VERSION 5.7 ;
BUSBITCHARS "[]" ;
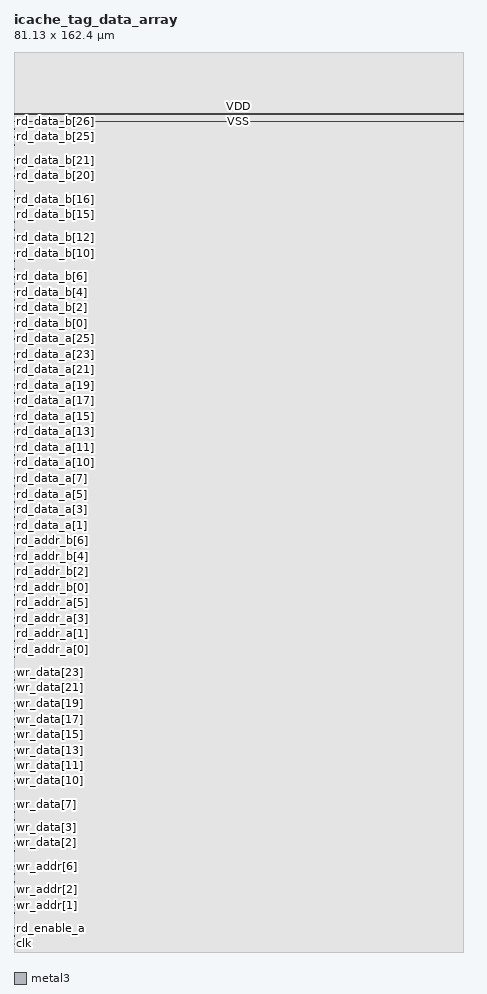
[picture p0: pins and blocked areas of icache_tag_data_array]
MACRO icache_tag_data_array
  FOREIGN icache_tag_data_array 0 0 ;
  SYMMETRY X Y R90 ;
  SIZE 81.130 BY 162.400 ;
  CLASS BLOCK ;
  PIN clk
    DIRECTION INPUT ;
    USE SIGNAL ;
    SHAPE ABUTMENT ;
    PORT
      LAYER metal3 ;
      RECT 0.000 1.400 0.140 1.540 ;
    END
  END clk
  PIN wr_enable
    DIRECTION INPUT ;
    USE SIGNAL ;
    SHAPE ABUTMENT ;
    PORT
      LAYER metal3 ;
      RECT 0.000 2.800 0.140 2.940 ;
    END
  END wr_enable
  PIN rd_enable_a
    DIRECTION INPUT ;
    USE SIGNAL ;
    SHAPE ABUTMENT ;
    PORT
      LAYER metal3 ;
      RECT 0.000 4.200 0.140 4.340 ;
    END
  END rd_enable_a
  PIN rd_enable_b
    DIRECTION INPUT ;
    USE SIGNAL ;
    SHAPE ABUTMENT ;
    PORT
      LAYER metal3 ;
      RECT 0.000 5.600 0.140 5.740 ;
    END
  END rd_enable_b
  PIN wr_addr[0]
    DIRECTION INPUT ;
    USE SIGNAL ;
    SHAPE ABUTMENT ;
    PORT
      LAYER metal3 ;
      RECT 0.000 7.000 0.140 7.140 ;
    END
  END wr_addr[0]
  PIN wr_addr[1]
    DIRECTION INPUT ;
    USE SIGNAL ;
    SHAPE ABUTMENT ;
    PORT
      LAYER metal3 ;
      RECT 0.000 8.400 0.140 8.540 ;
    END
  END wr_addr[1]
  PIN wr_addr[2]
    DIRECTION INPUT ;
    USE SIGNAL ;
    SHAPE ABUTMENT ;
    PORT
      LAYER metal3 ;
      RECT 0.000 9.800 0.140 9.940 ;
    END
  END wr_addr[2]
  PIN wr_addr[3]
    DIRECTION INPUT ;
    USE SIGNAL ;
    SHAPE ABUTMENT ;
    PORT
      LAYER metal3 ;
      RECT 0.000 11.200 0.140 11.340 ;
    END
  END wr_addr[3]
  PIN wr_addr[4]
    DIRECTION INPUT ;
    USE SIGNAL ;
    SHAPE ABUTMENT ;
    PORT
      LAYER metal3 ;
      RECT 0.000 12.600 0.140 12.740 ;
    END
  END wr_addr[4]
  PIN wr_addr[5]
    DIRECTION INPUT ;
    USE SIGNAL ;
    SHAPE ABUTMENT ;
    PORT
      LAYER metal3 ;
      RECT 0.000 14.000 0.140 14.140 ;
    END
  END wr_addr[5]
  PIN wr_addr[6]
    DIRECTION INPUT ;
    USE SIGNAL ;
    SHAPE ABUTMENT ;
    PORT
      LAYER metal3 ;
      RECT 0.000 15.400 0.140 15.540 ;
    END
  END wr_addr[6]
  PIN wr_data[0]
    DIRECTION INPUT ;
    USE SIGNAL ;
    SHAPE ABUTMENT ;
    PORT
      LAYER metal3 ;
      RECT 0.000 16.800 0.140 16.940 ;
    END
  END wr_data[0]
  PIN wr_data[1]
    DIRECTION INPUT ;
    USE SIGNAL ;
    SHAPE ABUTMENT ;
    PORT
      LAYER metal3 ;
      RECT 0.000 18.200 0.140 18.340 ;
    END
  END wr_data[1]
  PIN wr_data[2]
    DIRECTION INPUT ;
    USE SIGNAL ;
    SHAPE ABUTMENT ;
    PORT
      LAYER metal3 ;
      RECT 0.000 19.600 0.140 19.740 ;
    END
  END wr_data[2]
  PIN wr_data[3]
    DIRECTION INPUT ;
    USE SIGNAL ;
    SHAPE ABUTMENT ;
    PORT
      LAYER metal3 ;
      RECT 0.000 21.000 0.140 21.140 ;
    END
  END wr_data[3]
  PIN wr_data[4]
    DIRECTION INPUT ;
    USE SIGNAL ;
    SHAPE ABUTMENT ;
    PORT
      LAYER metal3 ;
      RECT 0.000 22.400 0.140 22.540 ;
    END
  END wr_data[4]
  PIN wr_data[5]
    DIRECTION INPUT ;
    USE SIGNAL ;
    SHAPE ABUTMENT ;
    PORT
      LAYER metal3 ;
      RECT 0.000 23.800 0.140 23.940 ;
    END
  END wr_data[5]
  PIN wr_data[6]
    DIRECTION INPUT ;
    USE SIGNAL ;
    SHAPE ABUTMENT ;
    PORT
      LAYER metal3 ;
      RECT 0.000 25.200 0.140 25.340 ;
    END
  END wr_data[6]
  PIN wr_data[7]
    DIRECTION INPUT ;
    USE SIGNAL ;
    SHAPE ABUTMENT ;
    PORT
      LAYER metal3 ;
      RECT 0.000 26.600 0.140 26.740 ;
    END
  END wr_data[7]
  PIN wr_data[8]
    DIRECTION INPUT ;
    USE SIGNAL ;
    SHAPE ABUTMENT ;
    PORT
      LAYER metal3 ;
      RECT 0.000 28.000 0.140 28.140 ;
    END
  END wr_data[8]
  PIN wr_data[9]
    DIRECTION INPUT ;
    USE SIGNAL ;
    SHAPE ABUTMENT ;
    PORT
      LAYER metal3 ;
      RECT 0.000 29.400 0.140 29.540 ;
    END
  END wr_data[9]
  PIN wr_data[10]
    DIRECTION INPUT ;
    USE SIGNAL ;
    SHAPE ABUTMENT ;
    PORT
      LAYER metal3 ;
      RECT 0.000 30.800 0.140 30.940 ;
    END
  END wr_data[10]
  PIN wr_data[11]
    DIRECTION INPUT ;
    USE SIGNAL ;
    SHAPE ABUTMENT ;
    PORT
      LAYER metal3 ;
      RECT 0.000 32.200 0.140 32.340 ;
    END
  END wr_data[11]
  PIN wr_data[12]
    DIRECTION INPUT ;
    USE SIGNAL ;
    SHAPE ABUTMENT ;
    PORT
      LAYER metal3 ;
      RECT 0.000 33.600 0.140 33.740 ;
    END
  END wr_data[12]
  PIN wr_data[13]
    DIRECTION INPUT ;
    USE SIGNAL ;
    SHAPE ABUTMENT ;
    PORT
      LAYER metal3 ;
      RECT 0.000 35.000 0.140 35.140 ;
    END
  END wr_data[13]
  PIN wr_data[14]
    DIRECTION INPUT ;
    USE SIGNAL ;
    SHAPE ABUTMENT ;
    PORT
      LAYER metal3 ;
      RECT 0.000 36.400 0.140 36.540 ;
    END
  END wr_data[14]
  PIN wr_data[15]
    DIRECTION INPUT ;
    USE SIGNAL ;
    SHAPE ABUTMENT ;
    PORT
      LAYER metal3 ;
      RECT 0.000 37.800 0.140 37.940 ;
    END
  END wr_data[15]
  PIN wr_data[16]
    DIRECTION INPUT ;
    USE SIGNAL ;
    SHAPE ABUTMENT ;
    PORT
      LAYER metal3 ;
      RECT 0.000 39.200 0.140 39.340 ;
    END
  END wr_data[16]
  PIN wr_data[17]
    DIRECTION INPUT ;
    USE SIGNAL ;
    SHAPE ABUTMENT ;
    PORT
      LAYER metal3 ;
      RECT 0.000 40.600 0.140 40.740 ;
    END
  END wr_data[17]
  PIN wr_data[18]
    DIRECTION INPUT ;
    USE SIGNAL ;
    SHAPE ABUTMENT ;
    PORT
      LAYER metal3 ;
      RECT 0.000 42.000 0.140 42.140 ;
    END
  END wr_data[18]
  PIN wr_data[19]
    DIRECTION INPUT ;
    USE SIGNAL ;
    SHAPE ABUTMENT ;
    PORT
      LAYER metal3 ;
      RECT 0.000 43.400 0.140 43.540 ;
    END
  END wr_data[19]
  PIN wr_data[20]
    DIRECTION INPUT ;
    USE SIGNAL ;
    SHAPE ABUTMENT ;
    PORT
      LAYER metal3 ;
      RECT 0.000 44.800 0.140 44.940 ;
    END
  END wr_data[20]
  PIN wr_data[21]
    DIRECTION INPUT ;
    USE SIGNAL ;
    SHAPE ABUTMENT ;
    PORT
      LAYER metal3 ;
      RECT 0.000 46.200 0.140 46.340 ;
    END
  END wr_data[21]
  PIN wr_data[22]
    DIRECTION INPUT ;
    USE SIGNAL ;
    SHAPE ABUTMENT ;
    PORT
      LAYER metal3 ;
      RECT 0.000 47.600 0.140 47.740 ;
    END
  END wr_data[22]
  PIN wr_data[23]
    DIRECTION INPUT ;
    USE SIGNAL ;
    SHAPE ABUTMENT ;
    PORT
      LAYER metal3 ;
      RECT 0.000 49.000 0.140 49.140 ;
    END
  END wr_data[23]
  PIN wr_data[24]
    DIRECTION INPUT ;
    USE SIGNAL ;
    SHAPE ABUTMENT ;
    PORT
      LAYER metal3 ;
      RECT 0.000 50.400 0.140 50.540 ;
    END
  END wr_data[24]
  PIN wr_data[25]
    DIRECTION INPUT ;
    USE SIGNAL ;
    SHAPE ABUTMENT ;
    PORT
      LAYER metal3 ;
      RECT 0.000 51.800 0.140 51.940 ;
    END
  END wr_data[25]
  PIN wr_data[26]
    DIRECTION INPUT ;
    USE SIGNAL ;
    SHAPE ABUTMENT ;
    PORT
      LAYER metal3 ;
      RECT 0.000 53.200 0.140 53.340 ;
    END
  END wr_data[26]
  PIN rd_addr_a[0]
    DIRECTION INPUT ;
    USE SIGNAL ;
    SHAPE ABUTMENT ;
    PORT
      LAYER metal3 ;
      RECT 0.000 54.600 0.140 54.740 ;
    END
  END rd_addr_a[0]
  PIN rd_addr_a[1]
    DIRECTION INPUT ;
    USE SIGNAL ;
    SHAPE ABUTMENT ;
    PORT
      LAYER metal3 ;
      RECT 0.000 56.000 0.140 56.140 ;
    END
  END rd_addr_a[1]
  PIN rd_addr_a[2]
    DIRECTION INPUT ;
    USE SIGNAL ;
    SHAPE ABUTMENT ;
    PORT
      LAYER metal3 ;
      RECT 0.000 57.400 0.140 57.540 ;
    END
  END rd_addr_a[2]
  PIN rd_addr_a[3]
    DIRECTION INPUT ;
    USE SIGNAL ;
    SHAPE ABUTMENT ;
    PORT
      LAYER metal3 ;
      RECT 0.000 58.800 0.140 58.940 ;
    END
  END rd_addr_a[3]
  PIN rd_addr_a[4]
    DIRECTION INPUT ;
    USE SIGNAL ;
    SHAPE ABUTMENT ;
    PORT
      LAYER metal3 ;
      RECT 0.000 60.200 0.140 60.340 ;
    END
  END rd_addr_a[4]
  PIN rd_addr_a[5]
    DIRECTION INPUT ;
    USE SIGNAL ;
    SHAPE ABUTMENT ;
    PORT
      LAYER metal3 ;
      RECT 0.000 61.600 0.140 61.740 ;
    END
  END rd_addr_a[5]
  PIN rd_addr_a[6]
    DIRECTION INPUT ;
    USE SIGNAL ;
    SHAPE ABUTMENT ;
    PORT
      LAYER metal3 ;
      RECT 0.000 63.000 0.140 63.140 ;
    END
  END rd_addr_a[6]
  PIN rd_addr_b[0]
    DIRECTION INPUT ;
    USE SIGNAL ;
    SHAPE ABUTMENT ;
    PORT
      LAYER metal3 ;
      RECT 0.000 64.400 0.140 64.540 ;
    END
  END rd_addr_b[0]
  PIN rd_addr_b[1]
    DIRECTION INPUT ;
    USE SIGNAL ;
    SHAPE ABUTMENT ;
    PORT
      LAYER metal3 ;
      RECT 0.000 65.800 0.140 65.940 ;
    END
  END rd_addr_b[1]
  PIN rd_addr_b[2]
    DIRECTION INPUT ;
    USE SIGNAL ;
    SHAPE ABUTMENT ;
    PORT
      LAYER metal3 ;
      RECT 0.000 67.200 0.140 67.340 ;
    END
  END rd_addr_b[2]
  PIN rd_addr_b[3]
    DIRECTION INPUT ;
    USE SIGNAL ;
    SHAPE ABUTMENT ;
    PORT
      LAYER metal3 ;
      RECT 0.000 68.600 0.140 68.740 ;
    END
  END rd_addr_b[3]
  PIN rd_addr_b[4]
    DIRECTION INPUT ;
    USE SIGNAL ;
    SHAPE ABUTMENT ;
    PORT
      LAYER metal3 ;
      RECT 0.000 70.000 0.140 70.140 ;
    END
  END rd_addr_b[4]
  PIN rd_addr_b[5]
    DIRECTION INPUT ;
    USE SIGNAL ;
    SHAPE ABUTMENT ;
    PORT
      LAYER metal3 ;
      RECT 0.000 71.400 0.140 71.540 ;
    END
  END rd_addr_b[5]
  PIN rd_addr_b[6]
    DIRECTION INPUT ;
    USE SIGNAL ;
    SHAPE ABUTMENT ;
    PORT
      LAYER metal3 ;
      RECT 0.000 72.800 0.140 72.940 ;
    END
  END rd_addr_b[6]
  PIN rd_data_a[0]
    DIRECTION OUTPUT ;
    USE SIGNAL ;
    SHAPE ABUTMENT ;
    PORT
      LAYER metal3 ;
      RECT 0.000 74.200 0.140 74.340 ;
    END
  END rd_data_a[0]
  PIN rd_data_a[1]
    DIRECTION OUTPUT ;
    USE SIGNAL ;
    SHAPE ABUTMENT ;
    PORT
      LAYER metal3 ;
      RECT 0.000 75.600 0.140 75.740 ;
    END
  END rd_data_a[1]
  PIN rd_data_a[2]
    DIRECTION OUTPUT ;
    USE SIGNAL ;
    SHAPE ABUTMENT ;
    PORT
      LAYER metal3 ;
      RECT 0.000 77.000 0.140 77.140 ;
    END
  END rd_data_a[2]
  PIN rd_data_a[3]
    DIRECTION OUTPUT ;
    USE SIGNAL ;
    SHAPE ABUTMENT ;
    PORT
      LAYER metal3 ;
      RECT 0.000 78.400 0.140 78.540 ;
    END
  END rd_data_a[3]
  PIN rd_data_a[4]
    DIRECTION OUTPUT ;
    USE SIGNAL ;
    SHAPE ABUTMENT ;
    PORT
      LAYER metal3 ;
      RECT 0.000 79.800 0.140 79.940 ;
    END
  END rd_data_a[4]
  PIN rd_data_a[5]
    DIRECTION OUTPUT ;
    USE SIGNAL ;
    SHAPE ABUTMENT ;
    PORT
      LAYER metal3 ;
      RECT 0.000 81.200 0.140 81.340 ;
    END
  END rd_data_a[5]
  PIN rd_data_a[6]
    DIRECTION OUTPUT ;
    USE SIGNAL ;
    SHAPE ABUTMENT ;
    PORT
      LAYER metal3 ;
      RECT 0.000 82.600 0.140 82.740 ;
    END
  END rd_data_a[6]
  PIN rd_data_a[7]
    DIRECTION OUTPUT ;
    USE SIGNAL ;
    SHAPE ABUTMENT ;
    PORT
      LAYER metal3 ;
      RECT 0.000 84.000 0.140 84.140 ;
    END
  END rd_data_a[7]
  PIN rd_data_a[8]
    DIRECTION OUTPUT ;
    USE SIGNAL ;
    SHAPE ABUTMENT ;
    PORT
      LAYER metal3 ;
      RECT 0.000 85.400 0.140 85.540 ;
    END
  END rd_data_a[8]
  PIN rd_data_a[9]
    DIRECTION OUTPUT ;
    USE SIGNAL ;
    SHAPE ABUTMENT ;
    PORT
      LAYER metal3 ;
      RECT 0.000 86.800 0.140 86.940 ;
    END
  END rd_data_a[9]
  PIN rd_data_a[10]
    DIRECTION OUTPUT ;
    USE SIGNAL ;
    SHAPE ABUTMENT ;
    PORT
      LAYER metal3 ;
      RECT 0.000 88.200 0.140 88.340 ;
    END
  END rd_data_a[10]
  PIN rd_data_a[11]
    DIRECTION OUTPUT ;
    USE SIGNAL ;
    SHAPE ABUTMENT ;
    PORT
      LAYER metal3 ;
      RECT 0.000 89.600 0.140 89.740 ;
    END
  END rd_data_a[11]
  PIN rd_data_a[12]
    DIRECTION OUTPUT ;
    USE SIGNAL ;
    SHAPE ABUTMENT ;
    PORT
      LAYER metal3 ;
      RECT 0.000 91.000 0.140 91.140 ;
    END
  END rd_data_a[12]
  PIN rd_data_a[13]
    DIRECTION OUTPUT ;
    USE SIGNAL ;
    SHAPE ABUTMENT ;
    PORT
      LAYER metal3 ;
      RECT 0.000 92.400 0.140 92.540 ;
    END
  END rd_data_a[13]
  PIN rd_data_a[14]
    DIRECTION OUTPUT ;
    USE SIGNAL ;
    SHAPE ABUTMENT ;
    PORT
      LAYER metal3 ;
      RECT 0.000 93.800 0.140 93.940 ;
    END
  END rd_data_a[14]
  PIN rd_data_a[15]
    DIRECTION OUTPUT ;
    USE SIGNAL ;
    SHAPE ABUTMENT ;
    PORT
      LAYER metal3 ;
      RECT 0.000 95.200 0.140 95.340 ;
    END
  END rd_data_a[15]
  PIN rd_data_a[16]
    DIRECTION OUTPUT ;
    USE SIGNAL ;
    SHAPE ABUTMENT ;
    PORT
      LAYER metal3 ;
      RECT 0.000 96.600 0.140 96.740 ;
    END
  END rd_data_a[16]
  PIN rd_data_a[17]
    DIRECTION OUTPUT ;
    USE SIGNAL ;
    SHAPE ABUTMENT ;
    PORT
      LAYER metal3 ;
      RECT 0.000 98.000 0.140 98.140 ;
    END
  END rd_data_a[17]
  PIN rd_data_a[18]
    DIRECTION OUTPUT ;
    USE SIGNAL ;
    SHAPE ABUTMENT ;
    PORT
      LAYER metal3 ;
      RECT 0.000 99.400 0.140 99.540 ;
    END
  END rd_data_a[18]
  PIN rd_data_a[19]
    DIRECTION OUTPUT ;
    USE SIGNAL ;
    SHAPE ABUTMENT ;
    PORT
      LAYER metal3 ;
      RECT 0.000 100.800 0.140 100.940 ;
    END
  END rd_data_a[19]
  PIN rd_data_a[20]
    DIRECTION OUTPUT ;
    USE SIGNAL ;
    SHAPE ABUTMENT ;
    PORT
      LAYER metal3 ;
      RECT 0.000 102.200 0.140 102.340 ;
    END
  END rd_data_a[20]
  PIN rd_data_a[21]
    DIRECTION OUTPUT ;
    USE SIGNAL ;
    SHAPE ABUTMENT ;
    PORT
      LAYER metal3 ;
      RECT 0.000 103.600 0.140 103.740 ;
    END
  END rd_data_a[21]
  PIN rd_data_a[22]
    DIRECTION OUTPUT ;
    USE SIGNAL ;
    SHAPE ABUTMENT ;
    PORT
      LAYER metal3 ;
      RECT 0.000 105.000 0.140 105.140 ;
    END
  END rd_data_a[22]
  PIN rd_data_a[23]
    DIRECTION OUTPUT ;
    USE SIGNAL ;
    SHAPE ABUTMENT ;
    PORT
      LAYER metal3 ;
      RECT 0.000 106.400 0.140 106.540 ;
    END
  END rd_data_a[23]
  PIN rd_data_a[24]
    DIRECTION OUTPUT ;
    USE SIGNAL ;
    SHAPE ABUTMENT ;
    PORT
      LAYER metal3 ;
      RECT 0.000 107.800 0.140 107.940 ;
    END
  END rd_data_a[24]
  PIN rd_data_a[25]
    DIRECTION OUTPUT ;
    USE SIGNAL ;
    SHAPE ABUTMENT ;
    PORT
      LAYER metal3 ;
      RECT 0.000 109.200 0.140 109.340 ;
    END
  END rd_data_a[25]
  PIN rd_data_a[26]
    DIRECTION OUTPUT ;
    USE SIGNAL ;
    SHAPE ABUTMENT ;
    PORT
      LAYER metal3 ;
      RECT 0.000 110.600 0.140 110.740 ;
    END
  END rd_data_a[26]
  PIN rd_data_b[0]
    DIRECTION OUTPUT ;
    USE SIGNAL ;
    SHAPE ABUTMENT ;
    PORT
      LAYER metal3 ;
      RECT 0.000 112.000 0.140 112.140 ;
    END
  END rd_data_b[0]
  PIN rd_data_b[1]
    DIRECTION OUTPUT ;
    USE SIGNAL ;
    SHAPE ABUTMENT ;
    PORT
      LAYER metal3 ;
      RECT 0.000 113.400 0.140 113.540 ;
    END
  END rd_data_b[1]
  PIN rd_data_b[2]
    DIRECTION OUTPUT ;
    USE SIGNAL ;
    SHAPE ABUTMENT ;
    PORT
      LAYER metal3 ;
      RECT 0.000 114.800 0.140 114.940 ;
    END
  END rd_data_b[2]
  PIN rd_data_b[3]
    DIRECTION OUTPUT ;
    USE SIGNAL ;
    SHAPE ABUTMENT ;
    PORT
      LAYER metal3 ;
      RECT 0.000 116.200 0.140 116.340 ;
    END
  END rd_data_b[3]
  PIN rd_data_b[4]
    DIRECTION OUTPUT ;
    USE SIGNAL ;
    SHAPE ABUTMENT ;
    PORT
      LAYER metal3 ;
      RECT 0.000 117.600 0.140 117.740 ;
    END
  END rd_data_b[4]
  PIN rd_data_b[5]
    DIRECTION OUTPUT ;
    USE SIGNAL ;
    SHAPE ABUTMENT ;
    PORT
      LAYER metal3 ;
      RECT 0.000 119.000 0.140 119.140 ;
    END
  END rd_data_b[5]
  PIN rd_data_b[6]
    DIRECTION OUTPUT ;
    USE SIGNAL ;
    SHAPE ABUTMENT ;
    PORT
      LAYER metal3 ;
      RECT 0.000 120.400 0.140 120.540 ;
    END
  END rd_data_b[6]
  PIN rd_data_b[7]
    DIRECTION OUTPUT ;
    USE SIGNAL ;
    SHAPE ABUTMENT ;
    PORT
      LAYER metal3 ;
      RECT 0.000 121.800 0.140 121.940 ;
    END
  END rd_data_b[7]
  PIN rd_data_b[8]
    DIRECTION OUTPUT ;
    USE SIGNAL ;
    SHAPE ABUTMENT ;
    PORT
      LAYER metal3 ;
      RECT 0.000 123.200 0.140 123.340 ;
    END
  END rd_data_b[8]
  PIN rd_data_b[9]
    DIRECTION OUTPUT ;
    USE SIGNAL ;
    SHAPE ABUTMENT ;
    PORT
      LAYER metal3 ;
      RECT 0.000 124.600 0.140 124.740 ;
    END
  END rd_data_b[9]
  PIN rd_data_b[10]
    DIRECTION OUTPUT ;
    USE SIGNAL ;
    SHAPE ABUTMENT ;
    PORT
      LAYER metal3 ;
      RECT 0.000 126.000 0.140 126.140 ;
    END
  END rd_data_b[10]
  PIN rd_data_b[11]
    DIRECTION OUTPUT ;
    USE SIGNAL ;
    SHAPE ABUTMENT ;
    PORT
      LAYER metal3 ;
      RECT 0.000 127.400 0.140 127.540 ;
    END
  END rd_data_b[11]
  PIN rd_data_b[12]
    DIRECTION OUTPUT ;
    USE SIGNAL ;
    SHAPE ABUTMENT ;
    PORT
      LAYER metal3 ;
      RECT 0.000 128.800 0.140 128.940 ;
    END
  END rd_data_b[12]
  PIN rd_data_b[13]
    DIRECTION OUTPUT ;
    USE SIGNAL ;
    SHAPE ABUTMENT ;
    PORT
      LAYER metal3 ;
      RECT 0.000 130.200 0.140 130.340 ;
    END
  END rd_data_b[13]
  PIN rd_data_b[14]
    DIRECTION OUTPUT ;
    USE SIGNAL ;
    SHAPE ABUTMENT ;
    PORT
      LAYER metal3 ;
      RECT 0.000 131.600 0.140 131.740 ;
    END
  END rd_data_b[14]
  PIN rd_data_b[15]
    DIRECTION OUTPUT ;
    USE SIGNAL ;
    SHAPE ABUTMENT ;
    PORT
      LAYER metal3 ;
      RECT 0.000 133.000 0.140 133.140 ;
    END
  END rd_data_b[15]
  PIN rd_data_b[16]
    DIRECTION OUTPUT ;
    USE SIGNAL ;
    SHAPE ABUTMENT ;
    PORT
      LAYER metal3 ;
      RECT 0.000 134.400 0.140 134.540 ;
    END
  END rd_data_b[16]
  PIN rd_data_b[17]
    DIRECTION OUTPUT ;
    USE SIGNAL ;
    SHAPE ABUTMENT ;
    PORT
      LAYER metal3 ;
      RECT 0.000 135.800 0.140 135.940 ;
    END
  END rd_data_b[17]
  PIN rd_data_b[18]
    DIRECTION OUTPUT ;
    USE SIGNAL ;
    SHAPE ABUTMENT ;
    PORT
      LAYER metal3 ;
      RECT 0.000 137.200 0.140 137.340 ;
    END
  END rd_data_b[18]
  PIN rd_data_b[19]
    DIRECTION OUTPUT ;
    USE SIGNAL ;
    SHAPE ABUTMENT ;
    PORT
      LAYER metal3 ;
      RECT 0.000 138.600 0.140 138.740 ;
    END
  END rd_data_b[19]
  PIN rd_data_b[20]
    DIRECTION OUTPUT ;
    USE SIGNAL ;
    SHAPE ABUTMENT ;
    PORT
      LAYER metal3 ;
      RECT 0.000 140.000 0.140 140.140 ;
    END
  END rd_data_b[20]
  PIN rd_data_b[21]
    DIRECTION OUTPUT ;
    USE SIGNAL ;
    SHAPE ABUTMENT ;
    PORT
      LAYER metal3 ;
      RECT 0.000 141.400 0.140 141.540 ;
    END
  END rd_data_b[21]
  PIN rd_data_b[22]
    DIRECTION OUTPUT ;
    USE SIGNAL ;
    SHAPE ABUTMENT ;
    PORT
      LAYER metal3 ;
      RECT 0.000 142.800 0.140 142.940 ;
    END
  END rd_data_b[22]
  PIN rd_data_b[23]
    DIRECTION OUTPUT ;
    USE SIGNAL ;
    SHAPE ABUTMENT ;
    PORT
      LAYER metal3 ;
      RECT 0.000 144.200 0.140 144.340 ;
    END
  END rd_data_b[23]
  PIN rd_data_b[24]
    DIRECTION OUTPUT ;
    USE SIGNAL ;
    SHAPE ABUTMENT ;
    PORT
      LAYER metal3 ;
      RECT 0.000 145.600 0.140 145.740 ;
    END
  END rd_data_b[24]
  PIN rd_data_b[25]
    DIRECTION OUTPUT ;
    USE SIGNAL ;
    SHAPE ABUTMENT ;
    PORT
      LAYER metal3 ;
      RECT 0.000 147.000 0.140 147.140 ;
    END
  END rd_data_b[25]
  PIN rd_data_b[26]
    DIRECTION OUTPUT ;
    USE SIGNAL ;
    SHAPE ABUTMENT ;
    PORT
      LAYER metal3 ;
      RECT 0.000 148.400 0.140 148.540 ;
    END
  END rd_data_b[26]
  PIN VSS
    DIRECTION INOUT ;
    USE GROUND ;
    SHAPE ABUTMENT ;
    PORT
      LAYER metal3 ;
      RECT 0.000 149.800 81.130 149.940 ;
    END
  END VSS
  PIN VDD
    DIRECTION INOUT ;
    USE POWER ;
    SHAPE ABUTMENT ;
    PORT
      LAYER metal3 ;
      RECT 0.000 151.200 81.130 151.340 ;
    END
  END VDD
  OBS
    LAYER metal1 ;
      RECT 0.000 0.000 81.130 162.400 ;
    LAYER metal2 ;
      RECT 0.000 0.000 81.130 162.400 ;
    LAYER metal3 ;
      RECT 0.000 0.000 81.130 162.400 ;
    LAYER metal4 ;
      RECT 0.000 0.000 81.130 162.400 ;
  END
END icache_tag_data_array
END LIBRARY
